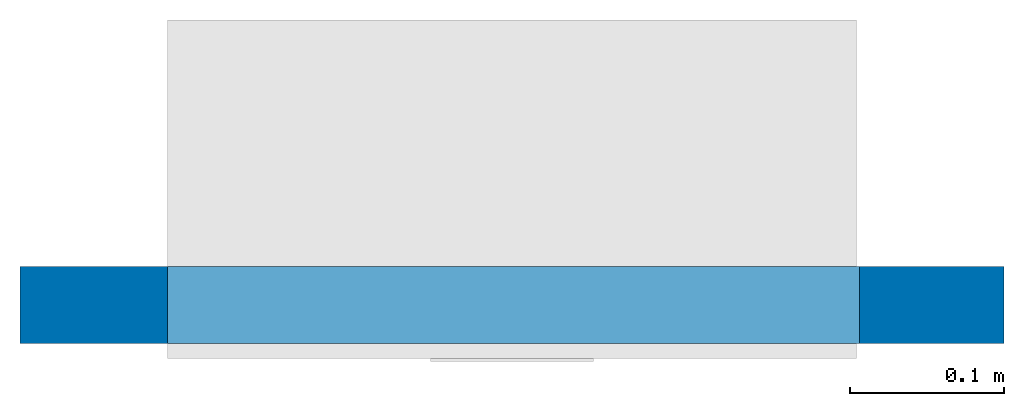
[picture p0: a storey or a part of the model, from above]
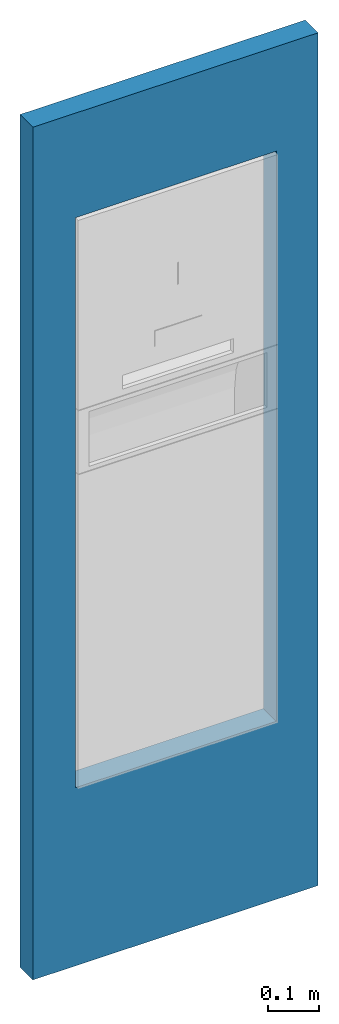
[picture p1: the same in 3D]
Properties of the parts of a building model (IFC2X3)

# File
Description: ViewDefinition [CoordinationView]
Time: 2018-01-31T10:30:36
Written by: The EXPRESS Data Manager Version 5.01.0100.02.64mod : 6 Jun 2012
Made in: 20140709_2115(x64) - Exporter 2014.0.2014.0709 - Default UI
Comment: STEP Physical File produced by: The EXPRESS Data Manager Version 5.01.0100.02.64mod : 6 Jun 2012 * Module: EDMstepFileFactory/EDMstandAlone * Creation date: Wed Jan 31 10:30:36 2018 * Host: BIM-HP * Database: C:\Users\dcole\AppData\Local\Temp\{6ED49666-5165-4591-B369-DF52BABB3398}\ifc * Database version: 5507 * Database creation date: Wed Jan 31 10:30:35 2018 * Schema: IFC2X3 * Model: DataRepository.ifc * Model creation date: Wed Jan 31 10:30:35 2018 * Header model: DataRepository.ifc_HeaderModel * Header model creation date: Wed Jan 31 10:30:35 2018 * EDMuser: sdai-user * EDMgroup: sdai-group * License ID and type: 5605 : Permanent license. Expiry date: * EDMstepFileFactory options: 020000

# IfcProject
LongName: P:\Fastrack\53721_DOLPHIN SOLUTIONS LIMITED\ADDITIONAL DRAWINGS 2018 BIM\IFC\DP4310.ifc

# IfcSite, Default
RefLatitude: 42, 24, 53, 508911; RefLongitude: -71, -15, -29, -58837; RefElevation: 0 mm

# IfcBuilding
Pset_BuildingCommon - NumberOfStoreys: 1

# IfcBuildingStorey, Level 1
LongName: Level 1; Elevation: 0 mm
Constraints - Elevation Base: Project Base Point; Elevation: 0 mm
Identity Data - Structural: no; Name: Level 1; Building Story: yes
Dimensions - Computation Height: 0 mm
Graphics - Line Pattern: -3000010; Symbol at End 1 Default: no; Color: 0; Line Weight: 1; Symbol at End 2 Default: yes

# IfcBuildingElementProxy: DP4310 Dolphin Combination Paper Towel and Waste Bin Touch Free, DP4310:DP4310 Dolphin Combination Paper Towel and Waste Bin Touch Free:75847
In: Level 1
Material: Glass
Phasing - Phase Created: New Construction
Constraints - Offset: 36.0482 mm; Moves With Nearby Elements: no; Host: Level : Level 1; Level: Level: Level 1
Dimensions - Volume: 0.0142429 m3; Height: 1348mm; Width: 448mm; Projection: 10mm; Recess: 1350 x 450 x 210mm
Pset_ManufacturerTypeInformation - Manufacturer: Dolphin Solutions Ltd.
Pset_BuildingElementProxyCommon - Reference: DP4310 Dolphin Combination Paper Towel and Waste Bin Touch Free
Identity Data - Manufacturer: Dolphin Solutions Ltd.; Description: Combination paper towel and waste bin touch free; Address: Southpoint, Compass Park, Junction Raod, Bodiam, TN32 5BS; Tel No.: +44 (0) 1424 202224; Assembly Description: Bath & Toilet Accessories - Residential; URL: www.dolphinsolutions.co.uk; Fax No.: +44 (0) 1424 205200; Model: DP4310; Email: info@dolphinsolutions.co.uk; Assembly Code: C1030220
General - Product Data: Superior quality and timeless design for prestigious washrooms. The combination comprises an electronic paper roll dispenser and a waste bin. Full metal housing in robust, easy-to-clean stainless steel AISI 304, satin finished, all corners fully welded. Combination lockable with cylinder locks using the same key. Inspection slot to indicate refill level. Dispenser for refilling and door for waste bin swing out. Electronic paper roll dispenser designed for paper rolls 215 mm width, inner diameter 50 mm and outer diameter up to 180 mm. Paper length infinitely adjustable by electronic control from 20 cm up to 120 cm, factory setting 45 cm. Residual roll function allows reserve roll to be put in operation before residual roll is completely used up. Touch-free, capacitive sensor technology, sensor distance 3.5 cm adjustable idle time 1s–5 s factory setting 1s Transformer - or battery powered options available. Supply voltage: 230 V, 50 Hz (WP 5455) or 4 x 1.5 V Mono/LR 20/13 A. Power rating 7w Waste bin capacity approx 48 litres, with removable mesh basket. Waste deposited from top. Also available upon request in a polished finish or with other surfaces.; Product Page Link: www.dolphinsolutions.co.uk/product/combination-paper-towel-and-waste-bin-touch-free
Electrical - Power Source: 230V 50Hz (WP5455) or 4 x 1.5V Mono/LR 20/13 A. Power rating 7w

# IfcOpeningElement: Opening
In: Level 1
Constraints - Base is Attached: no; Base Extension Distance: 0 mm; Room Bounding: yes; Related to Mass: no; Top is Attached: no; Unconnected Height: 2022.2 mm; Top Offset: 0 mm; Base Offset: -389.2 mm; Top Extension Distance: 0 mm; Base Constraint: Level: Level 1; Location Line: Finish Face: Interior
Dimensions - Length: 640 mm; Volume: 0.0342885 m3; Area: 0.68577 m2
Phasing - Phase Created: New Construction
Structural - Structural Usage: Non-bearing; Structural: no; Enable Analytical Model: no
Construction - Width: 50 mm; Function: Exterior; Wrapping at Inserts: Do not wrap
Analytical Properties - Absorptance: 0.1; Roughness: 1
Graphics - Coarse Scale Fill Color: 8454143

# IfcWallStandardCase: Basic Wall:Wall 1, Basic Wall:Wall 1:3092
In: Level 1
Type - PredefinedType: STANDARD; Material: Default Wall 50 mm
Type - Construction - Width: 50 mm; Function: Exterior; Wrapping at Inserts: Do not wrap
Type - Analytical Properties - Absorptance: 0.1; Roughness: 1
Type - Graphics - Coarse Scale Fill Color: 8454143
Constraints - Base is Attached: no; Base Extension Distance: 0 mm; Room Bounding: yes; Related to Mass: no; Top is Attached: no; Unconnected Height: 2022.2 mm; Top Offset: 0 mm; Base Offset: -389.2 mm; Top Extension Distance: 0 mm; Base Constraint: Level: Level 1; Location Line: Finish Face: Interior
Dimensions - Length: 640 mm; Volume: 0.0342885 m3; Area: 0.68577 m2
Phasing - Phase Created: New Construction
Structural - Structural Usage: Non-bearing; Structural: no; Enable Analytical Model: no
Pset_WallCommon - Reference: Wall 1; LoadBearing: no; ExtendToStructure: no; IsExternal: yes
